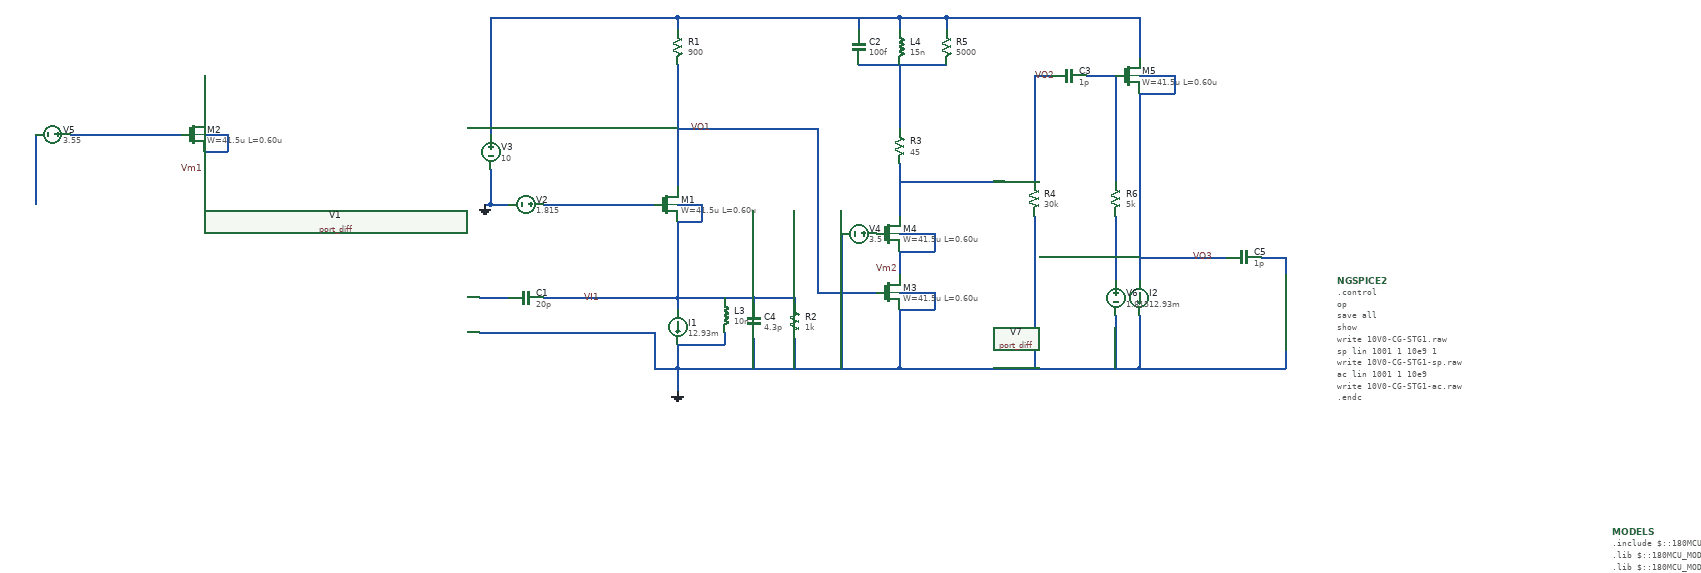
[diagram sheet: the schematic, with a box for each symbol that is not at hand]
v {xschem version=3.4.8RC file_version=1.3}
G {}
K {}
V {}
S {}
F {}
E {}
B 2 1030 440 1830 840 {flags=graph
y1=-15.4
y2=-8.5
ypos1=0
ypos2=2
divy=5
subdivy=1
unity=1
x1=1.2725754e+09
x2=5.3685754e+09
divx=5
subdivx=1
xlabmag=1.0
ylabmag=1.0
legendmag=1.0
node="\\"s_1_1 abs() log10() 20 *\\""
color=21
dataset=-1
unitx=1
logx=0
logy=0
}
B 2 1030 40 1830 440 {flags=graph
y1=-14.724977
y2=33.685905
ypos1=0
ypos2=2
divy=5
subdivy=1
unity=1
x1=1.2725754e+09
x2=5.3685754e+09
divx=5
subdivx=1
xlabmag=1.0
ylabmag=1.0
legendmag=1.0
node="\\"s_2_1 abs() log10() 20 *\\""
color=21
dataset=-1
unitx=1
logx=0
logy=0
hilight_wave=-1}
B 2 1830 440 2630 840 {flags=graph
y1=-4.1
y2=11
ypos1=0
ypos2=2
divy=5
subdivy=4
unity=1
x1=1.2725754e+09
x2=5.3685754e+09
divx=5
subdivx=4
xlabmag=1.0
ylabmag=1.0
legendmag=1.0
node="\\"s_2_2 abs() log10() 20 *\\""
color=21
dataset=-1
unitx=1
logx=0
logy=0
cursor1_x=-1.937045e+08
hilight_wave=0}
B 2 -790 40 10 440 {flags=graph
y1=0.62
y2=8.3
ypos1=0
ypos2=2
divy=5
subdivy=1
unity=1
x1=1.2725754e+09
x2=5.3685754e+09
divx=5
subdivx=1
xlabmag=1.0
ylabmag=1.0
legendmag=1.0
node="nfmin
nf"
color="21 4"
dataset=-1
unitx=1
logx=0
logy=0
}
B 2 1830 40 2630 440 {flags=graph
y1=0.062
y2=3400
ypos1=0
ypos2=2
divy=5
subdivy=1
unity=1
x1=1.2725754e+09
x2=5.3685754e+09
divx=5
subdivx=1
xlabmag=1.0
ylabmag=1.0
legendmag=1.0
node="\\"z_2_2 abs()\\""
color=21
dataset=-1
unitx=1
logx=0
logy=0
}
B 2 230 440 1030 840 {flags=graph
y1=-0.008
y2=0.002
ypos1=0
ypos2=2
divy=5
subdivy=1
unity=1
x1=1.2725754e+09
x2=5.3685754e+09
divx=5
subdivx=1
xlabmag=1.0
ylabmag=1.0
legendmag=1.0
node="\\"vo1 abs() log10() 20 * dev()\\"
\\"vo2 abs() log10() 20 * dev()\\""
color="21 4"
dataset=-1
unitx=1
logx=0
logy=0
}
B 2 2810 -1320 3610 -920 {flags=graph
y1=5
y2=13.9
ypos1=0
ypos2=2
divy=5
subdivy=1
unity=1
x1=1.2725754e+09
x2=5.3685754e+09
divx=5
subdivx=8
xlabmag=1.0
ylabmag=1.0
legendmag=1.0
node="\\"vo1 abs() log10() 10 *\\"
\\"vo2 abs() log10() 10 *\\"
\\"vo3 abs() log10() 10 *\\""
color="21 4 12"
dataset=-1
unitx=1
logx=1
logy=0
}
B 2 1830 840 2630 1240 {flags=graph
y1=-171.14801
y2=174.45199
ypos1=0
ypos2=2
divy=5
subdivy=4
unity=1
x1=1.2725754e+09
x2=5.3685754e+09
divx=5
subdivx=4
xlabmag=1.0
ylabmag=1.0
legendmag=1.0
dataset=-1
unitx=1
logx=0
logy=0
cursor1_x=-1.937045e+08
color=4
node=ph(s_2_2)}
B 2 2630 840 3430 1240 {flags=graph
y1=0.62
y2=3.5
ypos1=0
ypos2=2
divy=5
subdivy=4
unity=1
x1=1.2725754e+09
x2=5.3685754e+09
divx=5
subdivx=4
xlabmag=1.0
ylabmag=1.0
legendmag=1.0
dataset=-1
unitx=1
logx=0
logy=0
cursor1_x=-1.937045e+08
color=4
node=s_2_2
hilight_wave=-1}
B 2 2630 40 3430 440 {flags=graph
y1=-180
y2=180
ypos1=0
ypos2=2
divy=5
subdivy=1
unity=1
x1=1.2725754e+09
x2=5.3685754e+09
divx=5
subdivx=1
xlabmag=1.0
ylabmag=1.0
legendmag=1.0
node=ph(z_2_2)
color=21
dataset=-1
unitx=1
logx=0
logy=0
}
B 2 120 -2290 920 -1890 {flags=graph
y1=-36.053012
y2=74.047468
ypos1=0
ypos2=2
divy=5
subdivy=1
unity=1
x1=1.2725754e+09
x2=5.3685754e+09
divx=5
subdivx=8
xlabmag=1.0
ylabmag=1.0
legendmag=1.0
node="\\"vo1 vi1 / abs() log10() 20 *\\"
\\"vo2 vo1 / abs() log10() 20 *\\"
\\"vo2 abs() log10() 20 *\\"
\\"vo3 abs() log10() 20 *\\""
color="21 5 4 12"
dataset=-1
unitx=1
logx=1
logy=0
hilight_wave=-1
hcursor1_y=10.559218}
N 0 -1130 0 -1110 {lab=VI1
}
N 0 -1050 0 -1010 {lab=0
}
N 0 -1010 0 -970 {lab=0
}
N -40 -1070 -40 -1010 {lab=0
}
N -40 -1010 0 -1010 {lab=0
}
N -320 -1290 -290 -1290 {lab=0
}
N -320 -1350 -320 -1290 {lab=0
}
N 0 -1290 40 -1290 {lab=VI1
}
N 40 -1290 40 -1260 {lab=VI1
}
N -70 -1290 -40 -1290 {lab=#net1
}
N -340 -1130 -290 -1130 {lab=VI1
}
N -340 -1070 -40 -1070 {lab=0
}
N -320 -1610 -160 -1610 {lab=#net2
}
N 0 -1260 0 -1130 {lab=VI1
}
N -230 -1130 0 -1130 {lab=VI1
}
N -330 -1290 -320 -1290 {lab=0
}
N 0 -1530 0 -1510 {lab=VO1
}
N 0 -1610 0 -1590 {lab=#net2
}
N -320 -1610 -320 -1410 {lab=#net2
}
N -810 -1410 -770 -1410 {lab=Vm1
spice_ignore=true}
N -770 -1410 -770 -1380 {lab=Vm1
spice_ignore=true}
N -810 -1380 -810 -1320 {lab=Vm1
spice_ignore=true}
N -810 -1510 -810 -1440 {lab=#net4
spice_ignore=true}
N -880 -1410 -850 -1410 {lab=#net5
spice_ignore=true}
N -1100 -1410 -1100 -1290 {lab=#net6
spice_ignore=true}
N 60 -1010 380 -1010 {lab=0
}
N 0 -1010 60 -1010 {lab=0
}
N -160 -1610 0 -1610 {lab=#net2
}
N -940 -1410 -880 -1410 {lab=#net5
spice_ignore=true}
N -1040 -1410 -1000 -1410 {lab=#net5
spice_ignore=true}
N -230 -1290 -190 -1290 {lab=#net1
}
N -130 -1290 -70 -1290 {lab=#net1
}
N -1000 -1410 -940 -1410 {lab=#net5
spice_ignore=true}
N -190 -1290 -130 -1290 {lab=#net1}
N -810 -1380 -770 -1380 {lab=Vm1
spice_ignore=true}
N 0 -1260 40 -1260 {lab=VI1}
N 130 -1060 130 -1010 {lab=0}
N 490 -1010 700 -1010 {lab=0}
N 380 -1010 490 -1010 {lab=0}
N 0 -1130 80 -1130 {lab=VI1}
N 80 -1070 80 -1050 {lab=0}
N 0 -1050 80 -1050 {lab=0}
N 130 -1130 130 -1120 {lab=VI1}
N 80 -1130 130 -1130 {lab=VI1}
N 200 -1130 200 -1120 {lab=VI1}
N 130 -1130 200 -1130 {lab=VI1}
N 200 -1060 200 -1010 {lab=0}
N -0 -1510 -0 -1320 {lab=VO1}
N 380 -1110 380 -1010 {lab=0}
N 380 -1140 440 -1140 {lab=0}
N 440 -1140 440 -1110 {lab=0}
N 380 -1110 440 -1110 {lab=0}
N 380 -1210 380 -1170 {lab=Vm2
}
N 380 -1240 440 -1240 {lab=Vm2
}
N 440 -1240 440 -1210 {lab=Vm2
}
N 380 -1210 440 -1210 {lab=Vm2
}
N 240 -1420 240 -1240 {lab=VO1}
N 220 -1420 240 -1420 {lab=VO1}
N 0 -1420 220 -1420 {lab=VO1}
N 0 -1610 380 -1610 {lab=#net2}
N 380 -1610 380 -1590 {lab=#net2}
N 380 -1530 380 -1420 {lab=#net3}
N 380 -1360 380 -1270 {lab=VO2
}
N 240 -1240 240 -1140 {lab=VO1}
N 240 -1140 340 -1140 {lab=VO1}
N 610 -1510 610 -1330 {lab=VO2}
N 380 -1330 610 -1330 {lab=VO2}
N 280 -1240 280 -1010 {lab=0
}
N 380 -1180 380 -1170 {lab=Vm2}
N 540 -1330 560 -1330 {lab=VO2}
N 380 -1360 380 -1330 {lab=VO2}
N 610 -1270 610 -1010 {lab=0}
N 610 -1010 620 -1010 {lab=0}
N 310 -1610 310 -1590 {lab=#net2}
N 310 -1530 390 -1530 {lab=#net3}
N 390 -1530 460 -1530 {lab=#net3}
N 380 -1610 460 -1610 {lab=#net2}
N 460 -1610 460 -1590 {lab=#net2}
N 790 -1610 790 -1540 {lab=#net2}
N 460 -1610 790 -1610 {lab=#net2}
N 700 -1510 750 -1510 {lab=#net4}
N 790 -1510 850 -1510 {lab=VO3}
N 850 -1510 850 -1480 {lab=VO3}
N 790 -1480 850 -1480 {lab=VO3}
N 790 -1480 790 -1160 {lab=VO3}
N 790 -1100 790 -1010 {lab=0}
N 700 -1010 790 -1010 {lab=0}
N 1040 -1200 1040 -1170 {lab=#net5}
N 1040 -1110 1040 -1010 {lab=0}
N 790 -1010 1040 -1010 {lab=0}
N 610 -1510 640 -1510 {lab=VO2}
N 750 -1100 750 -1010 {lab=0}
N 750 -1270 750 -1160 {lab=#net6}
N 750 -1510 750 -1330 {lab=#net4}
N 1000 -1200 1040 -1200 {lab=#net5}
N 790 -1200 940 -1200 {lab=VO3}
C {devices/code_shown.sym} 1600 -730 0 0 {name=MODELS only_toplevel=true
format="tcleval( @value )"
value="
.include $::180MCU_MODELS/design.ngspice
.lib $::180MCU_MODELS/sm141064.ngspice typical
.lib $::180MCU_MODELS/smbb000149.ngspice typical
"}
C {symbols/nfet_10v0_asym.sym} -20 -1290 0 0 {name=M1
L=0.60u
W=41.5u
nf=10
m=5
ad="'W * 1.48u'"
pd="'2 * (W + 1.48u)'"
as="'W * 0.48u'"
ps="'2 * (W + 0.48u)'"
nrd=0 nrs=0
sa=0 sb=0 sd=0
model=nfet_10v0_asym
spiceprefix=X
}
C {gnd.sym} 0 -970 0 0 {name=l1 lab=0
}
C {port_diff.sym} -340 -1100 0 0 {name=V1 portnum=1 Z0=50 DCval=0 ACmag=2 ACphase=0 TRANval=""
}
C {vsource.sym} -260 -1290 1 0 {name=V2 value=1.815 savecurrent=false
}
C {gnd.sym} -330 -1290 1 0 {name=l2 lab=0
}
C {vsource.sym} -320 -1380 0 1 {name=V3 value=10 savecurrent=false
}
C {devices/launcher.sym} 390 -120 0 0 {name=h1
descr="load op & annotate" 
tclcommand="xschem raw_read $netlist_dir/10V0-CG-STG1.raw; set show_hidden_texts 1; xschem annotate_op"}
C {capa.sym} -260 -1130 3 0 {name=C1
m=1
value=20p
footprint=1206
device="ceramic capacitor"
spice_ignore=short}
C {isource.sym} 0 -1080 0 0 {name=I1 value=12.93m
spice_ignore=true}
C {res.sym} 0 -1560 0 0 {name=R1
value=900
footprint=1206
device=resistor
m=1
}
C {lab_wire.sym} -130 -1130 0 0 {name=p2 sig_type=std_logic lab=VI1
}
C {devices/code_shown.sym} 1130 -1160 0 0 {name=NGSPICE2 only_toplevel=true
value="
.control
op
save all
show
write 10V0-CG-STG1.raw
sp lin 1001 1 10e9 1
write 10V0-CG-STG1-sp.raw
ac lin 1001 1 10e9
write 10V0-CG-STG1-ac.raw
.endc
"
}
C {vsource.sym} -1070 -1410 1 0 {name=V5 value=3.55 savecurrent=false
spice_ignore=true}
C {lab_wire.sym} -810 -1350 0 0 {name=p3 sig_type=std_logic lab=Vm1
spice_ignore=true}
C {lab_wire.sym} 610 -1510 0 1 {name=p6 sig_type=std_logic lab=VO2
}
C {port_diff.sym} 1040 -1140 0 1 {name=V7 portnum=2 Z0=50 DCval=0 ACmag=0 ACphase=0 TRANval=""
}
C {symbols/nfet_10v0_asym.sym} -830 -1410 0 0 {name=M2
L=0.60u
W=41.5u
nf=10
m=5
ad="'W * 1.48u'"
pd="'2 * (W + 1.48u)'"
as="'W * 0.48u'"
ps="'2 * (W + 0.48u)'"
nrd=0 nrs=0
sa=0 sb=0 sd=0
model=nfet_10v0_asym
spiceprefix=X
spice_ignore=true}
C {ind.sym} 80 -1100 0 0 {name=L3
m=1
value=10n
footprint=1206
device=inductor
}
C {capa.sym} 130 -1090 0 0 {name=C4
m=1
value=4.3p
footprint=1206
device="ceramic capacitor"
spice_ignore=true}
C {res.sym} 200 -1090 0 0 {name=R2
value=1k
footprint=1206
device=resistor
m=1
spice_ignore=true}
C {symbols/nfet_10v0_asym.sym} 360 -1140 0 0 {name=M3
L=0.60u
W=41.5u
nf=10
m=10
ad="'W * 1.48u'"
pd="'2 * (W + 1.48u)'"
as="'W * 0.48u'"
ps="'2 * (W + 0.48u)'"
nrd=0 nrs=0
sa=0 sb=0 sd=0
model=nfet_10v0_asym
spiceprefix=X
}
C {symbols/nfet_10v0_asym.sym} 360 -1240 0 0 {name=M4
L=0.60u
W=41.5u
nf=10
m=2
ad="'W * 1.48u'"
pd="'2 * (W + 1.48u)'"
as="'W * 0.48u'"
ps="'2 * (W + 0.48u)'"
nrd=0 nrs=0
sa=0 sb=0 sd=0
model=nfet_10v0_asym
spiceprefix=X
}
C {ind.sym} 380 -1560 0 0 {name=L4
m=1
value=15n
footprint=1206
device=inductor
}
C {res.sym} 380 -1390 0 0 {name=R3
value=45
footprint=1206
device=resistor
m=1
}
C {vsource.sym} 310 -1240 1 0 {name=V4 value=3.5 savecurrent=false
}
C {lab_wire.sym} 60 -1420 0 0 {name=p1 sig_type=std_logic lab=VO1
}
C {lab_wire.sym} 380 -1180 0 0 {name=p4 sig_type=std_logic lab=Vm2
}
C {res.sym} 610 -1300 0 0 {name=R4
value=30k
footprint=1206
device=resistor
m=1
spice_ignore=true}
C {capa.sym} 310 -1560 0 0 {name=C2
m=1
value=100f
footprint=1206
device="ceramic capacitor"
spice_ignore=true}
C {res.sym} 460 -1560 0 0 {name=R5
value=5000
footprint=1206
device=resistor
m=1
spice_ignore=true}
C {symbols/nfet_10v0_asym.sym} 770 -1510 0 0 {name=M5
L=0.60u
W=41.5u
nf=10
m=5
ad="'W * 1.48u'"
pd="'2 * (W + 1.48u)'"
as="'W * 0.48u'"
ps="'2 * (W + 0.48u)'"
nrd=0 nrs=0
sa=0 sb=0 sd=0
model=nfet_10v0_asym
spiceprefix=X
}
C {lab_wire.sym} 880 -1200 0 1 {name=p5 sig_type=std_logic lab=VO3
}
C {capa.sym} 670 -1510 1 0 {name=C3
m=1
value=1p
footprint=1206
device="ceramic capacitor"
}
C {isource.sym} 790 -1130 0 0 {name=I2 value=12.93m
}
C {vsource.sym} 750 -1130 0 1 {name=V6 value=1.815 savecurrent=false
}
C {res.sym} 750 -1300 0 0 {name=R6
value=5k
footprint=1206
device=resistor
m=1
}
C {capa.sym} 970 -1200 1 0 {name=C5
m=1
value=1p
footprint=1206
device="ceramic capacitor"
}
